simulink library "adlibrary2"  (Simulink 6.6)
undefined symbols (not defined in the file or in its folder): adlibrary2, ADM, DDRII, DRAM, II, no_bitstream, SRAM, SX, XP, XRC
libraries: xbsIndex_r4 x430, adlibrary2 x11, adlibrary2_ddr2dram5t1_1 x6, adlibrary2_d2sram_0 x5, adlibrary2_ddr2dram_1 x4, adlibrary2_ddr_xpi0 x4, adlibrary2_ddr_xpl x3, adlibrary2_xpl32 x1, adlibrary2_xpl64 x1, adlibrary2_zbt64 x1, adlibrary2_zbt4_0 x1, adlibrary2_zbt4_1 x1
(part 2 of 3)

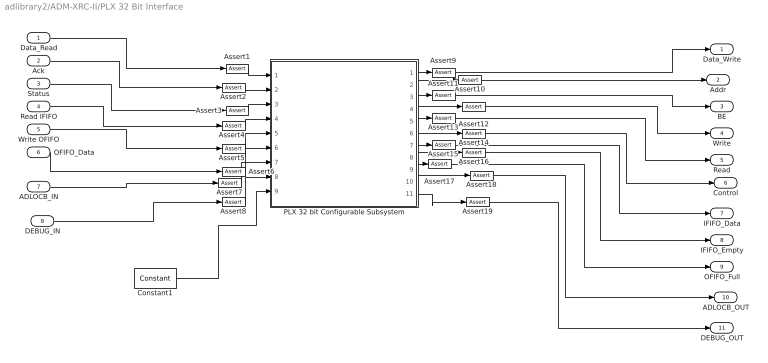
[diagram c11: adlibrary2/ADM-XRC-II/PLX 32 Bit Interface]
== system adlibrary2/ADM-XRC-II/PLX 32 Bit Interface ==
  Data_Read : Inport
  Ack : Inport  Port=2
  Status : Inport  Port=3
  Read IFIFO : Inport  Port=4
  Write OFIFO : Inport  Port=5
  OFIFO_Data : Inport  Port=6
  ADLOCB_IN : Inport  Port=7
  DEBUG_IN : Inport  Port=8
  Assert{1..19} (19 alike) : xbsIndex_r4/Assert  assert_type=off  type_source=Explicitly  arith_type="Signed  (2's comp)"  n_bits=16  bin_pt=14  assert_rate=on  rate_source=Explicitly  period=ad_get_simulink_period  output_port=on  block_type=assert
  Constant1 : xbsIndex_r4/Constant  arith_type=Boolean  const=sstep_clk_sel_default  n_bits=16  bin_pt=14  explicit_period=on  period=ad_get_simulink_period  equ=P=C  opselect=C  inp2=PCIN>>17  opr=+  inp1=P  carry=CIN  dbl_ovrd=off  block_type=constant
  PLX 32 bit Configurable Subsystem : Subsystem  Tag=configX  BlockChoice=PLX 32Bit Simulation  mask{program=program, clock_ratio=clock_ratio}
      mask prompts: program "Local Bus Script Program"; clock_ratio "Clock Ratio"
  Data_Write : Outport
  Addr : Outport  Port=2
  BE : Outport  Port=3
  Write : Outport  Port=4
  Read : Outport  Port=5
  Control : Outport  Port=6
  IFIFO_Data : Outport  Port=7
  IFIFO_Empty : Outport  Port=8
  OFIFO_Full : Outport  Port=9
  ADLOCB_OUT : Outport  Port=10
  DEBUG_OUT : Outport  Port=11
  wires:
  PLX 32 bit Configurable Subsystem/1(Data_Write) -> Assert9/1
  PLX 32 bit Configurable Subsystem/2(Addr) -> Assert10/1
  PLX 32 bit Configurable Subsystem/4(Write) -> Assert12/1
  PLX 32 bit Configurable Subsystem/6(Control) -> Assert14/1
  PLX 32 bit Configurable Subsystem/7(IFIFO_Data) -> Assert15/1
  PLX 32 bit Configurable Subsystem/8(IFIFO_Empty) -> Assert16/1
  PLX 32 bit Configurable Subsystem/9(OFIFO_Full) -> Assert17/1
  PLX 32 bit Configurable Subsystem/3(BE) -> Assert11/1
  PLX 32 bit Configurable Subsystem/10(ADLOCB_OUT) -> Assert18/1
  Data_Read/1 -> Assert1/1
  Ack/1 -> Assert2/1
  Status/1 -> Assert3/1
  Read IFIFO/1 -> Assert4/1
  Write OFIFO/1 -> Assert5/1
  OFIFO_Data/1 -> Assert6/1
  ADLOCB_IN/1 -> Assert7/1
  PLX 32 bit Configurable Subsystem/5(Read) -> Assert13/1
  Assert1/1 -> PLX 32 bit Configurable Subsystem/1(Data_Read)
  Assert2/1 -> PLX 32 bit Configurable Subsystem/2(Ack)
  Assert3/1 -> PLX 32 bit Configurable Subsystem/3(Status)
  Assert4/1 -> PLX 32 bit Configurable Subsystem/4(Read IFIFO)
  Assert5/1 -> PLX 32 bit Configurable Subsystem/5(Write OFIFO)
  Assert6/1 -> PLX 32 bit Configurable Subsystem/6(OFIFO_Data)
  Assert7/1 -> PLX 32 bit Configurable Subsystem/7(ADLOCB_IN)
  Assert9/1 -> Data_Write/1
  Assert10/1 -> Addr/1
  Assert11/1 -> BE/1
  Assert12/1 -> Write/1
  Assert13/1 -> Read/1
  Assert14/1 -> Control/1
  Assert15/1 -> IFIFO_Data/1
  Assert16/1 -> IFIFO_Empty/1
  Assert17/1 -> OFIFO_Full/1
  Assert18/1 -> ADLOCB_OUT/1
  DEBUG_IN/1 -> Assert8/1
  PLX 32 bit Configurable Subsystem/11(DEBUG_OUT) -> Assert19/1
  Assert19/1 -> DEBUG_OUT/1
  Assert8/1 -> PLX 32 bit Configurable Subsystem/8(DEBUG_IN)
  Constant1/1 -> PLX 32 bit Configurable Subsystem/9(sstep_clk_sel_default)

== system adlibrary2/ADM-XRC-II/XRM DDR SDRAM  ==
  cache_data_in : Inport
  cache_addr : Inport  Port=2
  cache_write : Inport  Port=3
  ddr_page : Inport  Port=4
  ddr_addr : Inport  Port=5
  ddr_read : Inport  Port=6
  ddr_write : Inport  Port=7
  Assert{1..9} (9 alike) : xbsIndex_r4/Assert  assert_type=off  type_source=Explicitly  arith_type="Signed  (2's comp)"  n_bits=16  bin_pt=14  assert_rate=on  rate_source=Explicitly  period=ad_get_simulink_period  output_port=on  block_type=assert
  Configurable Subsystem : Subsystem  Tag=configX  BlockChoice=DDR SDRAM 64bit Simulation
  cache_data_out : Outport
  ddr_busy : Outport  Port=2
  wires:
  cache_data_in/1 -> Assert1/1
  cache_addr/1 -> Assert2/1
  cache_write/1 -> Assert3/1
  ddr_page/1 -> Assert4/1
  ddr_addr/1 -> Assert5/1
  ddr_read/1 -> Assert6/1
  ddr_write/1 -> Assert7/1
  Configurable Subsystem/1(cache_data_out) -> Assert8/1
  Configurable Subsystem/2(ddr_busy) -> Assert9/1
  Assert1/1 -> Configurable Subsystem/1(cache_data_in)
  Assert2/1 -> Configurable Subsystem/2(cache_addr)
  Assert3/1 -> Configurable Subsystem/3(cache_write)
  Assert4/1 -> Configurable Subsystem/4(ddr_page)
  Assert5/1 -> Configurable Subsystem/5(ddr_addr)
  Assert6/1 -> Configurable Subsystem/6(ddr_read)
  Assert7/1 -> Configurable Subsystem/7(ddr_write)
  Assert8/1 -> cache_data_out/1
  Assert9/1 -> ddr_busy/1

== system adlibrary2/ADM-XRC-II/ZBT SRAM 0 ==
  d : Inport
  a : Inport  Port=2
  w : Inport  Port=3
  r : Inport  Port=4
  be : Inport  Port=5
  adlocb_in : Inport  Port=6
  Assert{,1..8} (9 alike) : xbsIndex_r4/Assert  assert_type=off  type_source=Explicitly  arith_type="Signed  (2's comp)"  n_bits=16  bin_pt=14  assert_rate=on  rate_source=Explicitly  period=ad_get_simulink_period  output_port=on  block_type=assert
  Configurable Subsystem : Subsystem  Tag=configX  BlockChoice=ZBT SRAM 32Bit Simulation
  q : Outport
  qv : Outport  Port=2
  adlocb_out : Outport  Port=3
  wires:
  d/1 -> Assert/1
  a/1 -> Assert1/1
  w/1 -> Assert2/1
  r/1 -> Assert4/1
  be/1 -> Assert3/1
  adlocb_in/1 -> Assert5/1
  Configurable Subsystem/1(q) -> Assert6/1
  Configurable Subsystem/2(qv) -> Assert7/1
  Configurable Subsystem/3(adlocb_out) -> Assert8/1
  Assert/1 -> Configurable Subsystem/1(d)
  Assert1/1 -> Configurable Subsystem/2(a)
  Assert2/1 -> Configurable Subsystem/3(w)
  Assert4/1 -> Configurable Subsystem/4(r)
  Assert3/1 -> Configurable Subsystem/5(be)
  Assert5/1 -> Configurable Subsystem/6(adlocb_in)
  Assert8/1 -> adlocb_out/1
  Assert7/1 -> qv/1
  Assert6/1 -> q/1

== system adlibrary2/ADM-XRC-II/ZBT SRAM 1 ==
  d : Inport
  a : Inport  Port=2
  w : Inport  Port=3
  r : Inport  Port=4
  be : Inport  Port=5
  adlocb_in : Inport  Port=6
  Assert{,1..8} (9 alike) : xbsIndex_r4/Assert  assert_type=off  type_source=Explicitly  arith_type="Signed  (2's comp)"  n_bits=16  bin_pt=14  assert_rate=on  rate_source=Explicitly  period=ad_get_simulink_period  output_port=on  block_type=assert
  Configurable Subsystem : Subsystem  Tag=configX  BlockChoice=ZBT SRAM 32Bit Simulation
  q : Outport
  qv : Outport  Port=2
  adlocb_out : Outport  Port=3
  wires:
  Configurable Subsystem/3(adlocb_out) -> Assert8/1
  Configurable Subsystem/2(qv) -> Assert7/1
  Configurable Subsystem/1(q) -> Assert6/1
  adlocb_in/1 -> Assert5/1
  be/1 -> Assert4/1
  r/1 -> Assert3/1
  w/1 -> Assert2/1
  a/1 -> Assert1/1
  d/1 -> Assert/1
  Assert/1 -> Configurable Subsystem/1(d)
  Assert1/1 -> Configurable Subsystem/2(a)
  Assert2/1 -> Configurable Subsystem/3(w)
  Assert3/1 -> Configurable Subsystem/4(r)
  Assert4/1 -> Configurable Subsystem/5(be)
  Assert5/1 -> Configurable Subsystem/6(adlocb_in)
  Assert6/1 -> q/1
  Assert7/1 -> qv/1
  Assert8/1 -> adlocb_out/1

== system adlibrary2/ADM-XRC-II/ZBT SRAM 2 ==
  d : Inport
  a : Inport  Port=2
  w : Inport  Port=3
  r : Inport  Port=4
  be : Inport  Port=5
  adlocb_in : Inport  Port=6
  Assert{,1..8} (9 alike) : xbsIndex_r4/Assert  assert_type=off  type_source=Explicitly  arith_type="Signed  (2's comp)"  n_bits=16  bin_pt=14  assert_rate=on  rate_source=Explicitly  period=ad_get_simulink_period  output_port=on  block_type=assert
  Configurable Subsystem : Subsystem  Tag=configX  BlockChoice=ZBT SRAM 32Bit Simulation
  q : Outport
  qv : Outport  Port=2
  adlocb_out : Outport  Port=3
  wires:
  Configurable Subsystem/3(adlocb_out) -> Assert8/1
  Configurable Subsystem/2(qv) -> Assert7/1
  Configurable Subsystem/1(q) -> Assert6/1
  adlocb_in/1 -> Assert5/1
  be/1 -> Assert4/1
  r/1 -> Assert3/1
  w/1 -> Assert2/1
  a/1 -> Assert1/1
  d/1 -> Assert/1
  Assert/1 -> Configurable Subsystem/1(d)
  Assert1/1 -> Configurable Subsystem/2(a)
  Assert2/1 -> Configurable Subsystem/3(w)
  Assert3/1 -> Configurable Subsystem/4(r)
  Assert4/1 -> Configurable Subsystem/5(be)
  Assert5/1 -> Configurable Subsystem/6(adlocb_in)
  Assert6/1 -> q/1
  Assert7/1 -> qv/1
  Assert8/1 -> adlocb_out/1

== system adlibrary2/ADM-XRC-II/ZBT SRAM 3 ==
  d : Inport
  a : Inport  Port=2
  w : Inport  Port=3
  r : Inport  Port=4
  be : Inport  Port=5
  adlocb_in : Inport  Port=6
  Assert{,1..8} (9 alike) : xbsIndex_r4/Assert  assert_type=off  type_source=Explicitly  arith_type="Signed  (2's comp)"  n_bits=16  bin_pt=14  assert_rate=on  rate_source=Explicitly  period=ad_get_simulink_period  output_port=on  block_type=assert
  Configurable Subsystem : Subsystem  Tag=configX  BlockChoice=ZBT SRAM 32Bit Simulation
  q : Outport
  qv : Outport  Port=2
  adlocb_out : Outport  Port=3
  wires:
  Configurable Subsystem/3(adlocb_out) -> Assert7/1
  Configurable Subsystem/2(qv) -> Assert6/1
  Configurable Subsystem/1(q) -> Assert8/1
  adlocb_in/1 -> Assert5/1
  be/1 -> Assert4/1
  r/1 -> Assert3/1
  w/1 -> Assert2/1
  a/1 -> Assert1/1
  d/1 -> Assert/1
  Assert/1 -> Configurable Subsystem/1(d)
  Assert1/1 -> Configurable Subsystem/2(a)
  Assert2/1 -> Configurable Subsystem/3(w)
  Assert3/1 -> Configurable Subsystem/4(r)
  Assert4/1 -> Configurable Subsystem/5(be)
  Assert5/1 -> Configurable Subsystem/6(adlocb_in)
  Assert8/1 -> q/1
  Assert6/1 -> qv/1
  ? -> adlocb_out/1

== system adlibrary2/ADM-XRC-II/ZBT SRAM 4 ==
  d : Inport
  a : Inport  Port=2
  w : Inport  Port=3
  r : Inport  Port=4
  be : Inport  Port=5
  adlocb_in : Inport  Port=6
  Assert{,1..8} (9 alike) : xbsIndex_r4/Assert  assert_type=off  type_source=Explicitly  arith_type="Signed  (2's comp)"  n_bits=16  bin_pt=14  assert_rate=on  rate_source=Explicitly  period=ad_get_simulink_period  output_port=on  block_type=assert
  Configurable Subsystem : Subsystem  Tag=configX  BlockChoice=ZBT SRAM 32Bit Simulation
  q : Outport
  qv : Outport  Port=2
  adlocb_out : Outport  Port=3
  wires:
  Configurable Subsystem/3(adlocb_out) -> Assert8/1
  Configurable Subsystem/2(qv) -> Assert7/1
  Configurable Subsystem/1(q) -> Assert6/1
  adlocb_in/1 -> Assert5/1
  be/1 -> Assert4/1
  r/1 -> Assert3/1
  w/1 -> Assert2/1
  a/1 -> Assert1/1
  d/1 -> Assert/1
  Assert/1 -> Configurable Subsystem/1(d)
  Assert1/1 -> Configurable Subsystem/2(a)
  Assert2/1 -> Configurable Subsystem/3(w)
  Assert3/1 -> Configurable Subsystem/4(r)
  Assert4/1 -> Configurable Subsystem/5(be)
  Assert5/1 -> Configurable Subsystem/6(adlocb_in)
  Assert6/1 -> q/1
  Assert7/1 -> qv/1
  Assert8/1 -> adlocb_out/1

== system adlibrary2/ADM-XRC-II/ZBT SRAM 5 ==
  d : Inport
  a : Inport  Port=2
  w : Inport  Port=3
  r : Inport  Port=4
  be : Inport  Port=5
  adlocb_in : Inport  Port=6
  Assert{,1..8} (9 alike) : xbsIndex_r4/Assert  assert_type=off  type_source=Explicitly  arith_type="Signed  (2's comp)"  n_bits=16  bin_pt=14  assert_rate=on  rate_source=Explicitly  period=ad_get_simulink_period  output_port=on  block_type=assert
  Configurable Subsystem : Subsystem  Tag=configX  BlockChoice=ZBT SRAM 32Bit Simulation
  q : Outport
  qv : Outport  Port=2
  adlocb_out : Outport  Port=3
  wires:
  Configurable Subsystem/3(adlocb_out) -> Assert8/1
  Configurable Subsystem/2(qv) -> Assert7/1
  Configurable Subsystem/1(q) -> Assert6/1
  adlocb_in/1 -> Assert5/1
  be/1 -> Assert4/1
  r/1 -> Assert3/1
  w/1 -> Assert2/1
  a/1 -> Assert1/1
  d/1 -> Assert/1
  Assert/1 -> Configurable Subsystem/1(d)
  Assert1/1 -> Configurable Subsystem/2(a)
  Assert2/1 -> Configurable Subsystem/3(w)
  Assert3/1 -> Configurable Subsystem/4(r)
  Assert4/1 -> Configurable Subsystem/5(be)
  Assert5/1 -> Configurable Subsystem/6(adlocb_in)
  Assert6/1 -> q/1
  Assert7/1 -> qv/1
  Assert8/1 -> adlocb_out/1

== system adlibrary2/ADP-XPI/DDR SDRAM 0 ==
  cache_data_in : Inport
  cache_addr : Inport  Port=2
  cache_write : Inport  Port=3
  ddr_page : Inport  Port=4
  ddr_addr : Inport  Port=5
  ddr_read : Inport  Port=6
  ddr_write : Inport  Port=7
  Assert{1..7,9..10} (9 alike) : xbsIndex_r4/Assert  assert_type=off  type_source=Explicitly  arith_type="Signed  (2's comp)"  n_bits=16  bin_pt=14  assert_rate=on  rate_source=Explicitly  period=ad_get_simulink_period  output_port=on  block_type=assert
  Configurable Subsystem : Subsystem  Tag=configX  BlockChoice=DDR SDRAM 64bit Simulation  mask{memsize=memsize}
      mask prompts: memsize "Simulation Ram Size (Mb)"
  cache_data_out : Outport
  ddr_busy : Outport  Port=2
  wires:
  Assert10/1 -> ddr_busy/1
  Assert9/1 -> cache_data_out/1
  Assert6/1 -> Configurable Subsystem/6(ddr_read)
  Assert5/1 -> Configurable Subsystem/5(ddr_addr)
  Assert4/1 -> Configurable Subsystem/4(ddr_page)
  Assert3/1 -> Configurable Subsystem/3(cache_write)
  Assert2/1 -> Configurable Subsystem/2(cache_addr)
  Assert1/1 -> Configurable Subsystem/1(cache_data_in)
  ddr_write/1 -> Assert7/1
  ddr_read/1 -> Assert6/1
  ddr_addr/1 -> Assert5/1
  ddr_page/1 -> Assert4/1
  cache_write/1 -> Assert3/1
  cache_addr/1 -> Assert2/1
  cache_data_in/1 -> Assert1/1
  Configurable Subsystem/1(cache_data_out) -> Assert9/1
  Configurable Subsystem/2(ddr_busy) -> Assert10/1
  Assert7/1 -> Configurable Subsystem/7(ddr_write)

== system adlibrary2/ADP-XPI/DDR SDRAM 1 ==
  cache_data_in : Inport
  cache_addr : Inport  Port=2
  cache_write : Inport  Port=3
  ddr_page : Inport  Port=4
  ddr_addr : Inport  Port=5
  ddr_read : Inport  Port=6
  ddr_write : Inport  Port=7
  Assert{1..7,9..10} (9 alike) : xbsIndex_r4/Assert  assert_type=off  type_source=Explicitly  arith_type="Signed  (2's comp)"  n_bits=16  bin_pt=14  assert_rate=on  rate_source=Explicitly  period=ad_get_simulink_period  output_port=on  block_type=assert
  Configurable Subsystem : Subsystem  Tag=configX  BlockChoice=DDR SDRAM 64bit Simulation  mask{memsize=memsize}
      mask prompts: memsize "Simulation Ram Size (Mb)"
  cache_data_out : Outport
  ddr_busy : Outport  Port=2
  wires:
  Assert7/1 -> Configurable Subsystem/7(ddr_write)
  Configurable Subsystem/2(ddr_busy) -> Assert10/1
  Configurable Subsystem/1(cache_data_out) -> Assert9/1
  cache_data_in/1 -> Assert1/1
  cache_addr/1 -> Assert2/1
  cache_write/1 -> Assert3/1
  ddr_page/1 -> Assert4/1
  ddr_addr/1 -> Assert5/1
  ddr_read/1 -> Assert6/1
  ddr_write/1 -> Assert7/1
  Assert1/1 -> Configurable Subsystem/1(cache_data_in)
  Assert2/1 -> Configurable Subsystem/2(cache_addr)
  Assert3/1 -> Configurable Subsystem/3(cache_write)
  Assert4/1 -> Configurable Subsystem/4(ddr_page)
  Assert5/1 -> Configurable Subsystem/5(ddr_addr)
  Assert6/1 -> Configurable Subsystem/6(ddr_read)
  Assert9/1 -> cache_data_out/1
  Assert10/1 -> ddr_busy/1

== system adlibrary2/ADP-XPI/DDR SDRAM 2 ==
  cache_data_in : Inport
  cache_addr : Inport  Port=2
  cache_write : Inport  Port=3
  ddr_page : Inport  Port=4
  ddr_addr : Inport  Port=5
  ddr_read : Inport  Port=6
  ddr_write : Inport  Port=7
  Assert{1..7,9..10} (9 alike) : xbsIndex_r4/Assert  assert_type=off  type_source=Explicitly  arith_type="Signed  (2's comp)"  n_bits=16  bin_pt=14  assert_rate=on  rate_source=Explicitly  period=ad_get_simulink_period  output_port=on  block_type=assert
  Configurable Subsystem : Subsystem  Tag=configX  BlockChoice=DDR SDRAM 64bit Simulation  mask{memsize=memsize}
      mask prompts: memsize "Simulation Ram Size (Mb)"
  cache_data_out : Outport
  ddr_busy : Outport  Port=2
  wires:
  Assert10/1 -> ddr_busy/1
  Assert9/1 -> cache_data_out/1
  Assert6/1 -> Configurable Subsystem/6(ddr_read)
  Assert5/1 -> Configurable Subsystem/5(ddr_addr)
  Assert4/1 -> Configurable Subsystem/4(ddr_page)
  Assert3/1 -> Configurable Subsystem/3(cache_write)
  Assert2/1 -> Configurable Subsystem/2(cache_addr)
  Assert1/1 -> Configurable Subsystem/1(cache_data_in)
  ddr_write/1 -> Assert7/1
  ddr_read/1 -> Assert6/1
  ddr_addr/1 -> Assert5/1
  ddr_page/1 -> Assert4/1
  cache_write/1 -> Assert3/1
  cache_addr/1 -> Assert2/1
  cache_data_in/1 -> Assert1/1
  Configurable Subsystem/1(cache_data_out) -> Assert9/1
  Configurable Subsystem/2(ddr_busy) -> Assert10/1
  Assert7/1 -> Configurable Subsystem/7(ddr_write)

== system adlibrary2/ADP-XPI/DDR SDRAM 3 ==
  cache_data_in : Inport
  cache_addr : Inport  Port=2
  cache_write : Inport  Port=3
  ddr_page : Inport  Port=4
  ddr_addr : Inport  Port=5
  ddr_read : Inport  Port=6
  ddr_write : Inport  Port=7
  Assert{1..7,9..10} (9 alike) : xbsIndex_r4/Assert  assert_type=off  type_source=Explicitly  arith_type="Signed  (2's comp)"  n_bits=16  bin_pt=14  assert_rate=on  rate_source=Explicitly  period=ad_get_simulink_period  output_port=on  block_type=assert
  Configurable Subsystem : Subsystem  Tag=configX  BlockChoice=DDR SDRAM 64bit Simulation  mask{memsize=memsize}
      mask prompts: memsize "Simulation Ram Size (Mb)"
  cache_data_out : Outport
  ddr_busy : Outport  Port=2
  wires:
  Assert7/1 -> Configurable Subsystem/7(ddr_write)
  Configurable Subsystem/2(ddr_busy) -> Assert10/1
  Configurable Subsystem/1(cache_data_out) -> Assert9/1
  cache_data_in/1 -> Assert1/1
  cache_addr/1 -> Assert2/1
  cache_write/1 -> Assert3/1
  ddr_page/1 -> Assert4/1
  ddr_addr/1 -> Assert5/1
  ddr_read/1 -> Assert6/1
  ddr_write/1 -> Assert7/1
  Assert1/1 -> Configurable Subsystem/1(cache_data_in)
  Assert2/1 -> Configurable Subsystem/2(cache_addr)
  Assert3/1 -> Configurable Subsystem/3(cache_write)
  Assert4/1 -> Configurable Subsystem/4(ddr_page)
  Assert5/1 -> Configurable Subsystem/5(ddr_addr)
  Assert6/1 -> Configurable Subsystem/6(ddr_read)
  Assert9/1 -> cache_data_out/1
  Assert10/1 -> ddr_busy/1

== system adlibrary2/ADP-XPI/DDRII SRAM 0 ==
  d : Inport
  a : Inport  Port=2
  w : Inport  Port=3
  r : Inport  Port=4
  be : Inport  Port=5
  adlocb_in : Inport  Port=6
  Assert{1..9} (9 alike) : xbsIndex_r4/Assert  assert_type=off  type_source=Explicitly  arith_type="Signed  (2's comp)"  n_bits=16  bin_pt=14  assert_rate=on  rate_source=Explicitly  period=ad_get_simulink_period  output_port=on  block_type=assert
  Configurable Subsystem : Subsystem  Tag=configX  BlockChoice=DDRII SRAM Simulation
  q : Outport
  qv : Outport  Port=2
  adlocb_out : Outport  Port=3
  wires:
  Assert9/1 -> adlocb_out/1
  Assert8/1 -> qv/1
  Assert7/1 -> q/1
  Assert6/1 -> Configurable Subsystem/6(adlocb_in)
  Assert5/1 -> Configurable Subsystem/5(be)
  Assert4/1 -> Configurable Subsystem/4(r)
  Assert3/1 -> Configurable Subsystem/3(w)
  Assert2/1 -> Configurable Subsystem/2(a)
  Assert1/1 -> Configurable Subsystem/1(d)
  Configurable Subsystem/2(qv) -> Assert8/1
  Configurable Subsystem/3(adlocb_out) -> Assert9/1
  adlocb_in/1 -> Assert6/1
  be/1 -> Assert5/1
  r/1 -> Assert4/1
  w/1 -> Assert3/1
  a/1 -> Assert2/1
  d/1 -> Assert1/1
  Configurable Subsystem/1(q) -> Assert7/1

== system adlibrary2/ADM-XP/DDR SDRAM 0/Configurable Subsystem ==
  cache_data_in : Inport
  cache_addr : Inport  Port=2
  cache_write : Inport  Port=3
  ddr_page : Inport  Port=4
  ddr_addr : Inport  Port=5
  ddr_read : Inport  Port=6
  ddr_write : Inport  Port=7
  adlocb_in : Inport  Port=8
  DDR SDRAM 32bit Simulation : adlibrary2_ddr_xpl/DDR SDRAM 32bit Simulation  SystemSampleTime=-1  memsize=memsize
  cache_data_out : Outport
  ddr_busy : Outport  Port=2
  adlocb_out : Outport  Port=3
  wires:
  cache_data_in/1 -> DDR SDRAM 32bit Simulation/1
  cache_addr/1 -> DDR SDRAM 32bit Simulation/2
  cache_write/1 -> DDR SDRAM 32bit Simulation/3
  ddr_page/1 -> DDR SDRAM 32bit Simulation/4
  ddr_addr/1 -> DDR SDRAM 32bit Simulation/5
  ddr_read/1 -> DDR SDRAM 32bit Simulation/6
  ddr_write/1 -> DDR SDRAM 32bit Simulation/7
  adlocb_in/1 -> DDR SDRAM 32bit Simulation/8
  DDR SDRAM 32bit Simulation/1 -> cache_data_out/1
  DDR SDRAM 32bit Simulation/2 -> ddr_busy/1
  DDR SDRAM 32bit Simulation/3 -> adlocb_out/1

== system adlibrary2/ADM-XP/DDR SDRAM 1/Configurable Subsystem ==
  cache_data_in : Inport
  cache_addr : Inport  Port=2
  cache_write : Inport  Port=3
  ddr_page : Inport  Port=4
  ddr_addr : Inport  Port=5
  ddr_read : Inport  Port=6
  ddr_write : Inport  Port=7
  adlocb_in : Inport  Port=8
  DDR SDRAM 32bit Simulation : adlibrary2_ddr_xpl/DDR SDRAM 32bit Simulation  SystemSampleTime=-1  memsize=memsize
  cache_data_out : Outport
  ddr_busy : Outport  Port=2
  adlocb_out : Outport  Port=3
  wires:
  cache_data_in/1 -> DDR SDRAM 32bit Simulation/1
  cache_addr/1 -> DDR SDRAM 32bit Simulation/2
  cache_write/1 -> DDR SDRAM 32bit Simulation/3
  ddr_page/1 -> DDR SDRAM 32bit Simulation/4
  ddr_addr/1 -> DDR SDRAM 32bit Simulation/5
  ddr_read/1 -> DDR SDRAM 32bit Simulation/6
  ddr_write/1 -> DDR SDRAM 32bit Simulation/7
  adlocb_in/1 -> DDR SDRAM 32bit Simulation/8
  DDR SDRAM 32bit Simulation/1 -> cache_data_out/1
  DDR SDRAM 32bit Simulation/2 -> ddr_busy/1
  DDR SDRAM 32bit Simulation/3 -> adlocb_out/1

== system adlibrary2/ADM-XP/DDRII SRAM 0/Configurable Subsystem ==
  d : Inport
  a : Inport  Port=2
  w : Inport  Port=3
  r : Inport  Port=4
  be : Inport  Port=5
  adlocb_in : Inport  Port=6
  DDRII SRAM Simulation : adlibrary2_d2sram_0/DDRII SRAM Simulation  SystemSampleTime=-1
  q : Outport
  qv : Outport  Port=2
  adlocb_out : Outport  Port=3
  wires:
  d/1 -> DDRII SRAM Simulation/1
  a/1 -> DDRII SRAM Simulation/2
  w/1 -> DDRII SRAM Simulation/3
  r/1 -> DDRII SRAM Simulation/4
  be/1 -> DDRII SRAM Simulation/5
  adlocb_in/1 -> DDRII SRAM Simulation/6
  DDRII SRAM Simulation/1 -> q/1
  DDRII SRAM Simulation/2 -> qv/1
  DDRII SRAM Simulation/3 -> adlocb_out/1

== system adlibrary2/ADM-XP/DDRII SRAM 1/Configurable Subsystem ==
  d : Inport
  a : Inport  Port=2
  w : Inport  Port=3
  r : Inport  Port=4
  be : Inport  Port=5
  adlocb_in : Inport  Port=6
  DDRII SRAM Simulation : adlibrary2_d2sram_0/DDRII SRAM Simulation  SystemSampleTime=-1
  q : Outport
  qv : Outport  Port=2
  adlocb_out : Outport  Port=3
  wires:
  d/1 -> DDRII SRAM Simulation/1
  a/1 -> DDRII SRAM Simulation/2
  w/1 -> DDRII SRAM Simulation/3
  r/1 -> DDRII SRAM Simulation/4
  be/1 -> DDRII SRAM Simulation/5
  adlocb_in/1 -> DDRII SRAM Simulation/6
  DDRII SRAM Simulation/1 -> q/1
  DDRII SRAM Simulation/2 -> qv/1
  DDRII SRAM Simulation/3 -> adlocb_out/1

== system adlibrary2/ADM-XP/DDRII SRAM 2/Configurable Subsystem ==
  d : Inport
  a : Inport  Port=2
  w : Inport  Port=3
  r : Inport  Port=4
  be : Inport  Port=5
  adlocb_in : Inport  Port=6
  DDRII SRAM Simulation : adlibrary2_d2sram_0/DDRII SRAM Simulation  SystemSampleTime=-1
  q : Outport
  qv : Outport  Port=2
  adlocb_out : Outport  Port=3
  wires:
  d/1 -> DDRII SRAM Simulation/1
  a/1 -> DDRII SRAM Simulation/2
  w/1 -> DDRII SRAM Simulation/3
  r/1 -> DDRII SRAM Simulation/4
  be/1 -> DDRII SRAM Simulation/5
  adlocb_in/1 -> DDRII SRAM Simulation/6
  DDRII SRAM Simulation/1 -> q/1
  DDRII SRAM Simulation/2 -> qv/1
  DDRII SRAM Simulation/3 -> adlocb_out/1

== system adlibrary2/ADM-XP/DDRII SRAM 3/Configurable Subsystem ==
  d : Inport
  a : Inport  Port=2
  w : Inport  Port=3
  r : Inport  Port=4
  be : Inport  Port=5
  adlocb_in : Inport  Port=6
  DDRII SRAM Simulation : adlibrary2_d2sram_0/DDRII SRAM Simulation  SystemSampleTime=-1
  q : Outport
  qv : Outport  Port=2
  adlocb_out : Outport  Port=3
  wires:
  d/1 -> DDRII SRAM Simulation/1
  a/1 -> DDRII SRAM Simulation/2
  w/1 -> DDRII SRAM Simulation/3
  r/1 -> DDRII SRAM Simulation/4
  be/1 -> DDRII SRAM Simulation/5
  adlocb_in/1 -> DDRII SRAM Simulation/6
  DDRII SRAM Simulation/1 -> q/1
  DDRII SRAM Simulation/2 -> qv/1
  DDRII SRAM Simulation/3 -> adlocb_out/1

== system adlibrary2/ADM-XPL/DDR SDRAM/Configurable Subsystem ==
  cache_data_in : Inport
  cache_addr : Inport  Port=2
  cache_write : Inport  Port=3
  ddr_page : Inport  Port=4
  ddr_addr : Inport  Port=5
  ddr_read : Inport  Port=6
  ddr_write : Inport  Port=7
  adlocb_in : Inport  Port=8
  DDR SDRAM 32bit Simulation : adlibrary2_ddr_xpl/DDR SDRAM 32bit Simulation  SystemSampleTime=-1  memsize=memsize
  cache_data_out : Outport
  ddr_busy : Outport  Port=2
  adlocb_out : Outport  Port=3
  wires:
  cache_data_in/1 -> DDR SDRAM 32bit Simulation/1
  cache_addr/1 -> DDR SDRAM 32bit Simulation/2
  cache_write/1 -> DDR SDRAM 32bit Simulation/3
  ddr_page/1 -> DDR SDRAM 32bit Simulation/4
  ddr_addr/1 -> DDR SDRAM 32bit Simulation/5
  ddr_read/1 -> DDR SDRAM 32bit Simulation/6
  ddr_write/1 -> DDR SDRAM 32bit Simulation/7
  adlocb_in/1 -> DDR SDRAM 32bit Simulation/8
  DDR SDRAM 32bit Simulation/1 -> cache_data_out/1
  DDR SDRAM 32bit Simulation/2 -> ddr_busy/1
  DDR SDRAM 32bit Simulation/3 -> adlocb_out/1

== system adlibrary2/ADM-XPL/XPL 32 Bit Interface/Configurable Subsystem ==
  Data_Read : Inport
  Ack : Inport  Port=2
  Status : Inport  Port=3
  Read IFIFO : Inport  Port=4
  Write OFIFO : Inport  Port=5
  OFIFO_Data : Inport  Port=6
  ADLOCB_IN : Inport  Port=7
  DEBUG_IN : Inport  Port=8
  sstep_clk_sel_default : Inport  Port=9
  XPL 32Bit Simulation : adlibrary2_xpl32/XPL 32Bit Simulation  SystemSampleTime=-1  program=program  clock_ratio=clock_ratio
  Data_Write : Outport
  Addr : Outport  Port=2
  BE : Outport  Port=3
  Write : Outport  Port=4
  Read : Outport  Port=5
  Control : Outport  Port=6
  IFIFO_Data : Outport  Port=7
  IFIFO_Empty : Outport  Port=8
  OFIFO_Full : Outport  Port=9
  ADLOCB_OUT : Outport  Port=10
  DEBUG_OUT : Outport  Port=11
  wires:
  Data_Read/1 -> XPL 32Bit Simulation/1
  Ack/1 -> XPL 32Bit Simulation/2
  Status/1 -> XPL 32Bit Simulation/3
  Read IFIFO/1 -> XPL 32Bit Simulation/4
  Write OFIFO/1 -> XPL 32Bit Simulation/5
  OFIFO_Data/1 -> XPL 32Bit Simulation/6
  ADLOCB_IN/1 -> XPL 32Bit Simulation/7
  DEBUG_IN/1 -> XPL 32Bit Simulation/8
  sstep_clk_sel_default/1 -> XPL 32Bit Simulation/9
  XPL 32Bit Simulation/1 -> Data_Write/1
  XPL 32Bit Simulation/2 -> Addr/1
  XPL 32Bit Simulation/3 -> BE/1
  XPL 32Bit Simulation/4 -> Write/1
  XPL 32Bit Simulation/5 -> Read/1
  XPL 32Bit Simulation/6 -> Control/1
  XPL 32Bit Simulation/7 -> IFIFO_Data/1
  XPL 32Bit Simulation/8 -> IFIFO_Empty/1
  XPL 32Bit Simulation/9 -> OFIFO_Full/1
  XPL 32Bit Simulation/10 -> ADLOCB_OUT/1
  XPL 32Bit Simulation/11 -> DEBUG_OUT/1

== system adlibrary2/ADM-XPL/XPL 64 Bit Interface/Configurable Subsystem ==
  Data_Read : Inport
  Ack : Inport  Port=2
  Status : Inport  Port=3
  Read IFIFO : Inport  Port=4
  Write OFIFO : Inport  Port=5
  OFIFO_Data : Inport  Port=6
  ADLOCB_IN : Inport  Port=7
  DEBUG_IN : Inport  Port=8
  sstep_clk_sel_default : Inport  Port=9
  XPL 64Bit Simulation : adlibrary2_xpl64/XPL 64Bit Simulation  SystemSampleTime=-1  program=program  clock_ratio=clock_ratio
  Data_Write : Outport
  Addr : Outport  Port=2
  BE : Outport  Port=3
  Write : Outport  Port=4
  Read : Outport  Port=5
  Control : Outport  Port=6
  IFIFO_Data : Outport  Port=7
  IFIFO_Empty : Outport  Port=8
  OFIFO_Full : Outport  Port=9
  ADLOCB_OUT : Outport  Port=10
  DEBUG_OUT : Outport  Port=11
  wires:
  Data_Read/1 -> XPL 64Bit Simulation/1
  Ack/1 -> XPL 64Bit Simulation/2
  Status/1 -> XPL 64Bit Simulation/3
  Read IFIFO/1 -> XPL 64Bit Simulation/4
  Write OFIFO/1 -> XPL 64Bit Simulation/5
  OFIFO_Data/1 -> XPL 64Bit Simulation/6
  ADLOCB_IN/1 -> XPL 64Bit Simulation/7
  DEBUG_IN/1 -> XPL 64Bit Simulation/8
  sstep_clk_sel_default/1 -> XPL 64Bit Simulation/9
  XPL 64Bit Simulation/1 -> Data_Write/1
  XPL 64Bit Simulation/2 -> Addr/1
  XPL 64Bit Simulation/3 -> BE/1
  XPL 64Bit Simulation/4 -> Write/1
  XPL 64Bit Simulation/5 -> Read/1
  XPL 64Bit Simulation/6 -> Control/1
  XPL 64Bit Simulation/7 -> IFIFO_Data/1
  XPL 64Bit Simulation/8 -> IFIFO_Empty/1
  XPL 64Bit Simulation/9 -> OFIFO_Full/1
  XPL 64Bit Simulation/10 -> ADLOCB_OUT/1
  XPL 64Bit Simulation/11 -> DEBUG_OUT/1

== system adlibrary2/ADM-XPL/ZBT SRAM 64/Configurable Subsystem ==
  d : Inport
  a : Inport  Port=2
  w : Inport  Port=3
  r : Inport  Port=4
  be : Inport  Port=5
  adlocb_in : Inport  Port=6
  ZBT SRAM 64bit Simulation : adlibrary2_zbt64/ZBT SRAM 64bit Simulation  SystemSampleTime=-1
  q : Outport
  qv : Outport  Port=2
  adlocb_out : Outport  Port=3
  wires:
  d/1 -> ZBT SRAM 64bit Simulation/1
  a/1 -> ZBT SRAM 64bit Simulation/2
  w/1 -> ZBT SRAM 64bit Simulation/3
  r/1 -> ZBT SRAM 64bit Simulation/4
  be/1 -> ZBT SRAM 64bit Simulation/5
  adlocb_in/1 -> ZBT SRAM 64bit Simulation/6
  ZBT SRAM 64bit Simulation/1 -> q/1
  ZBT SRAM 64bit Simulation/2 -> qv/1
  ZBT SRAM 64bit Simulation/3 -> adlocb_out/1

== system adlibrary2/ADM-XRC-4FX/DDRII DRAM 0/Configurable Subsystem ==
  d : Inport
  a : Inport  Port=2
  w : Inport  Port=3
  r : Inport  Port=4
  be : Inport  Port=5
  adlocb_in : Inport  Port=6
  DDRII DRAM Simulation : adlibrary2_ddr2dram_1/DDRII DRAM Simulation  SystemSampleTime=-1
  q : Outport
  qv : Outport  Port=2
  full : Outport  Port=3
  adlocb_out : Outport  Port=4
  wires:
  d/1 -> DDRII DRAM Simulation/1
  a/1 -> DDRII DRAM Simulation/2
  w/1 -> DDRII DRAM Simulation/3
  r/1 -> DDRII DRAM Simulation/4
  be/1 -> DDRII DRAM Simulation/5
  adlocb_in/1 -> DDRII DRAM Simulation/6
  DDRII DRAM Simulation/1 -> q/1
  DDRII DRAM Simulation/2 -> qv/1
  DDRII DRAM Simulation/3 -> full/1
  DDRII DRAM Simulation/4 -> adlocb_out/1

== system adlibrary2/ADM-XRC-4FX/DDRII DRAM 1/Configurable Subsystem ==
  d : Inport
  a : Inport  Port=2
  w : Inport  Port=3
  r : Inport  Port=4
  be : Inport  Port=5
  adlocb_in : Inport  Port=6
  DDRII DRAM Generation : adlibrary2_ddr2dram_1/DDRII DRAM Generation  SystemSampleTime=-1
  q : Outport
  qv : Outport  Port=2
  full : Outport  Port=3
  adlocb_out : Outport  Port=4
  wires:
  d/1 -> DDRII DRAM Generation/1
  a/1 -> DDRII DRAM Generation/2
  w/1 -> DDRII DRAM Generation/3
  r/1 -> DDRII DRAM Generation/4
  be/1 -> DDRII DRAM Generation/5
  adlocb_in/1 -> DDRII DRAM Generation/6
  DDRII DRAM Generation/1 -> q/1
  DDRII DRAM Generation/2 -> qv/1
  DDRII DRAM Generation/3 -> full/1
  DDRII DRAM Generation/4 -> adlocb_out/1

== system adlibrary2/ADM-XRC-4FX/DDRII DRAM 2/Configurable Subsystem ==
  d : Inport
  a : Inport  Port=2
  w : Inport  Port=3
  r : Inport  Port=4
  be : Inport  Port=5
  adlocb_in : Inport  Port=6
  DDRII DRAM Generation : adlibrary2_ddr2dram_1/DDRII DRAM Generation  SystemSampleTime=-1
  q : Outport
  qv : Outport  Port=2
  full : Outport  Port=3
  adlocb_out : Outport  Port=4
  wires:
  d/1 -> DDRII DRAM Generation/1
  a/1 -> DDRII DRAM Generation/2
  w/1 -> DDRII DRAM Generation/3
  r/1 -> DDRII DRAM Generation/4
  be/1 -> DDRII DRAM Generation/5
  adlocb_in/1 -> DDRII DRAM Generation/6
  DDRII DRAM Generation/1 -> q/1
  DDRII DRAM Generation/2 -> qv/1
  DDRII DRAM Generation/3 -> full/1
  DDRII DRAM Generation/4 -> adlocb_out/1

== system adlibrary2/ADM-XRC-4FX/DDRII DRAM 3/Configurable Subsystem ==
  d : Inport
  a : Inport  Port=2
  w : Inport  Port=3
  r : Inport  Port=4
  be : Inport  Port=5
  adlocb_in : Inport  Port=6
  DDRII DRAM Generation : adlibrary2_ddr2dram_1/DDRII DRAM Generation  SystemSampleTime=-1
  q : Outport
  qv : Outport  Port=2
  full : Outport  Port=3
  adlocb_out : Outport  Port=4
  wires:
  d/1 -> DDRII DRAM Generation/1
  a/1 -> DDRII DRAM Generation/2
  w/1 -> DDRII DRAM Generation/3
  r/1 -> DDRII DRAM Generation/4
  be/1 -> DDRII DRAM Generation/5
  adlocb_in/1 -> DDRII DRAM Generation/6
  DDRII DRAM Generation/1 -> q/1
  DDRII DRAM Generation/2 -> qv/1
  DDRII DRAM Generation/3 -> full/1
  DDRII DRAM Generation/4 -> adlocb_out/1

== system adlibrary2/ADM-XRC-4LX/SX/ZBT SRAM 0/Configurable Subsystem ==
  d : Inport
  a : Inport  Port=2
  w : Inport  Port=3
  r : Inport  Port=4
  be : Inport  Port=5
  adlocb_in : Inport  Port=6
  ZBT SRAM 32Bit Simulation : adlibrary2_zbt4_0/ZBT SRAM 32Bit Simulation  SystemSampleTime=-1
  q : Outport
  qv : Outport  Port=2
  adlocb_out : Outport  Port=3
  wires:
  d/1 -> ZBT SRAM 32Bit Simulation/1
  a/1 -> ZBT SRAM 32Bit Simulation/2
  w/1 -> ZBT SRAM 32Bit Simulation/3
  r/1 -> ZBT SRAM 32Bit Simulation/4
  be/1 -> ZBT SRAM 32Bit Simulation/5
  adlocb_in/1 -> ZBT SRAM 32Bit Simulation/6
  ZBT SRAM 32Bit Simulation/1 -> q/1
  ZBT SRAM 32Bit Simulation/2 -> qv/1
  ZBT SRAM 32Bit Simulation/3 -> adlocb_out/1

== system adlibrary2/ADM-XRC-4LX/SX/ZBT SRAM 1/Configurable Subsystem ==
  d : Inport
  a : Inport  Port=2
  w : Inport  Port=3
  r : Inport  Port=4
  be : Inport  Port=5
  adlocb_in : Inport  Port=6
  ZBT SRAM 32Bit Simulation : adlibrary2_zbt4_1/ZBT SRAM 32Bit Simulation  SystemSampleTime=-1
  q : Outport
  qv : Outport  Port=2
  adlocb_out : Outport  Port=3
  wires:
  d/1 -> ZBT SRAM 32Bit Simulation/1
  a/1 -> ZBT SRAM 32Bit Simulation/2
  w/1 -> ZBT SRAM 32Bit Simulation/3
  r/1 -> ZBT SRAM 32Bit Simulation/4
  be/1 -> ZBT SRAM 32Bit Simulation/5
  adlocb_in/1 -> ZBT SRAM 32Bit Simulation/6
  ZBT SRAM 32Bit Simulation/1 -> q/1
  ZBT SRAM 32Bit Simulation/2 -> qv/1
  ZBT SRAM 32Bit Simulation/3 -> adlocb_out/1

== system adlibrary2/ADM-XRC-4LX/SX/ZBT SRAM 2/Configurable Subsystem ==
  d : Inport
  a : Inport  Port=2
  w : Inport  Port=3
  r : Inport  Port=4
  be : Inport  Port=5
  adlocb_in : Inport  Port=6
  ZBT SRAM 32Bit Simulation : adlibrary2_zbt4_2/ZBT SRAM 32Bit Simulation  SystemSampleTime=-1
  q : Outport
  qv : Outport  Port=2
  adlocb_out : Outport  Port=3
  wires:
  d/1 -> ZBT SRAM 32Bit Simulation/1
  a/1 -> ZBT SRAM 32Bit Simulation/2
  w/1 -> ZBT SRAM 32Bit Simulation/3
  r/1 -> ZBT SRAM 32Bit Simulation/4
  be/1 -> ZBT SRAM 32Bit Simulation/5
  adlocb_in/1 -> ZBT SRAM 32Bit Simulation/6
  ZBT SRAM 32Bit Simulation/1 -> q/1
  ZBT SRAM 32Bit Simulation/2 -> qv/1
  ZBT SRAM 32Bit Simulation/3 -> adlocb_out/1

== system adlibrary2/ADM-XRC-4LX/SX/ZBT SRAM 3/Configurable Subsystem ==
  d : Inport
  a : Inport  Port=2
  w : Inport  Port=3
  r : Inport  Port=4
  be : Inport  Port=5
  adlocb_in : Inport  Port=6
  ZBT SRAM 32Bit Simulation : adlibrary2_zbt4_3/ZBT SRAM 32Bit Simulation  SystemSampleTime=-1
  q : Outport
  qv : Outport  Port=2
  adlocb_out : Outport  Port=3
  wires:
  d/1 -> ZBT SRAM 32Bit Simulation/1
  a/1 -> ZBT SRAM 32Bit Simulation/2
  w/1 -> ZBT SRAM 32Bit Simulation/3
  r/1 -> ZBT SRAM 32Bit Simulation/4
  be/1 -> ZBT SRAM 32Bit Simulation/5
  adlocb_in/1 -> ZBT SRAM 32Bit Simulation/6
  ZBT SRAM 32Bit Simulation/1 -> q/1
  ZBT SRAM 32Bit Simulation/2 -> qv/1
  ZBT SRAM 32Bit Simulation/3 -> adlocb_out/1

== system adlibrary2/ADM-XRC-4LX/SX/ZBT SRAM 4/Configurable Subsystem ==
  d : Inport
  a : Inport  Port=2
  w : Inport  Port=3
  r : Inport  Port=4
  be : Inport  Port=5
  adlocb_in : Inport  Port=6
  ZBT SRAM 32Bit Simulation : adlibrary2_zbt4_4/ZBT SRAM 32Bit Simulation  SystemSampleTime=-1
  q : Outport
  qv : Outport  Port=2
  adlocb_out : Outport  Port=3
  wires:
  d/1 -> ZBT SRAM 32Bit Simulation/1
  a/1 -> ZBT SRAM 32Bit Simulation/2
  w/1 -> ZBT SRAM 32Bit Simulation/3
  r/1 -> ZBT SRAM 32Bit Simulation/4
  be/1 -> ZBT SRAM 32Bit Simulation/5
  adlocb_in/1 -> ZBT SRAM 32Bit Simulation/6
  ZBT SRAM 32Bit Simulation/1 -> q/1
  ZBT SRAM 32Bit Simulation/2 -> qv/1
  ZBT SRAM 32Bit Simulation/3 -> adlocb_out/1

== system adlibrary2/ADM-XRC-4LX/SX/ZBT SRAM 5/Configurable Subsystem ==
  d : Inport
  a : Inport  Port=2
  w : Inport  Port=3
  r : Inport  Port=4
  be : Inport  Port=5
  adlocb_in : Inport  Port=6
  ZBT SRAM 32Bit Simulation : adlibrary2_zbt4_5/ZBT SRAM 32Bit Simulation  SystemSampleTime=-1
  q : Outport
  qv : Outport  Port=2
  adlocb_out : Outport  Port=3
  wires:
  d/1 -> ZBT SRAM 32Bit Simulation/1
  a/1 -> ZBT SRAM 32Bit Simulation/2
  w/1 -> ZBT SRAM 32Bit Simulation/3
  r/1 -> ZBT SRAM 32Bit Simulation/4
  be/1 -> ZBT SRAM 32Bit Simulation/5
  adlocb_in/1 -> ZBT SRAM 32Bit Simulation/6
  ZBT SRAM 32Bit Simulation/1 -> q/1
  ZBT SRAM 32Bit Simulation/2 -> qv/1
  ZBT SRAM 32Bit Simulation/3 -> adlocb_out/1

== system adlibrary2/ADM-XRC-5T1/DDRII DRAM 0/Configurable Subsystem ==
  d : Inport
  a : Inport  Port=2
  w : Inport  Port=3
  r : Inport  Port=4
  be : Inport  Port=5
  adlocb_in : Inport  Port=6
  DDRII DRAM Simulation : adlibrary2_ddr2dram5t1_1/DDRII DRAM Simulation  SystemSampleTime=-1
  q : Outport
  qv : Outport  Port=2
  full : Outport  Port=3
  adlocb_out : Outport  Port=4
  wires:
  d/1 -> DDRII DRAM Simulation/1
  a/1 -> DDRII DRAM Simulation/2
  w/1 -> DDRII DRAM Simulation/3
  r/1 -> DDRII DRAM Simulation/4
  be/1 -> DDRII DRAM Simulation/5
  adlocb_in/1 -> DDRII DRAM Simulation/6
  DDRII DRAM Simulation/1 -> q/1
  DDRII DRAM Simulation/2 -> qv/1
  DDRII DRAM Simulation/3 -> full/1
  DDRII DRAM Simulation/4 -> adlocb_out/1

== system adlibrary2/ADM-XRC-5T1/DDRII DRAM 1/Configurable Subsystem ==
  d : Inport
  a : Inport  Port=2
  w : Inport  Port=3
  r : Inport  Port=4
  be : Inport  Port=5
  adlocb_in : Inport  Port=6
  DDRII DRAM Simulation : adlibrary2_ddr2dram5t1_1/DDRII DRAM Simulation  SystemSampleTime=-1
  q : Outport
  qv : Outport  Port=2
  full : Outport  Port=3
  adlocb_out : Outport  Port=4
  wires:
  d/1 -> DDRII DRAM Simulation/1
  a/1 -> DDRII DRAM Simulation/2
  w/1 -> DDRII DRAM Simulation/3
  r/1 -> DDRII DRAM Simulation/4
  be/1 -> DDRII DRAM Simulation/5
  adlocb_in/1 -> DDRII DRAM Simulation/6
  DDRII DRAM Simulation/1 -> q/1
  DDRII DRAM Simulation/2 -> qv/1
  DDRII DRAM Simulation/3 -> full/1
  DDRII DRAM Simulation/4 -> adlocb_out/1

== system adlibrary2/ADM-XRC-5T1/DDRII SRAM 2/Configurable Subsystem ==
  d : Inport
  a : Inport  Port=2
  w : Inport  Port=3
  r : Inport  Port=4
  be : Inport  Port=5
  adlocb_in : Inport  Port=6
  DDRII DRAM Simulation : adlibrary2_ddr2sram5t1/DDRII DRAM Simulation  SystemSampleTime=-1
  q : Outport
  qv : Outport  Port=2
  full : Outport  Port=3
  adlocb_out : Outport  Port=4
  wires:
  d/1 -> DDRII DRAM Simulation/1
  a/1 -> DDRII DRAM Simulation/2
  w/1 -> DDRII DRAM Simulation/3
  r/1 -> DDRII DRAM Simulation/4
  be/1 -> DDRII DRAM Simulation/5
  adlocb_in/1 -> DDRII DRAM Simulation/6
  DDRII DRAM Simulation/1 -> q/1
  DDRII DRAM Simulation/2 -> qv/1
  DDRII DRAM Simulation/3 -> full/1
  DDRII DRAM Simulation/4 -> adlocb_out/1

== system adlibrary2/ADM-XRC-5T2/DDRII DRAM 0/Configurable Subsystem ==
  d : Inport
  a : Inport  Port=2
  w : Inport  Port=3
  r : Inport  Port=4
  be : Inport  Port=5
  adlocb_in : Inport  Port=6
  DDRII DRAM Simulation : adlibrary2_ddr2dram5t1_1/DDRII DRAM Simulation  SystemSampleTime=-1
  q : Outport
  qv : Outport  Port=2
  full : Outport  Port=3
  adlocb_out : Outport  Port=4
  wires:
  d/1 -> DDRII DRAM Simulation/1
  a/1 -> DDRII DRAM Simulation/2
  w/1 -> DDRII DRAM Simulation/3
  r/1 -> DDRII DRAM Simulation/4
  be/1 -> DDRII DRAM Simulation/5
  adlocb_in/1 -> DDRII DRAM Simulation/6
  DDRII DRAM Simulation/1 -> q/1
  DDRII DRAM Simulation/2 -> qv/1
  DDRII DRAM Simulation/3 -> full/1
  DDRII DRAM Simulation/4 -> adlocb_out/1

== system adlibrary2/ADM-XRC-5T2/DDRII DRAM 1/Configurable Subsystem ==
  d : Inport
  a : Inport  Port=2
  w : Inport  Port=3
  r : Inport  Port=4
  be : Inport  Port=5
  adlocb_in : Inport  Port=6
  DDRII DRAM Simulation : adlibrary2_ddr2dram5t1_1/DDRII DRAM Simulation  SystemSampleTime=-1
  q : Outport
  qv : Outport  Port=2
  full : Outport  Port=3
  adlocb_out : Outport  Port=4
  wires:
  d/1 -> DDRII DRAM Simulation/1
  a/1 -> DDRII DRAM Simulation/2
  w/1 -> DDRII DRAM Simulation/3
  r/1 -> DDRII DRAM Simulation/4
  be/1 -> DDRII DRAM Simulation/5
  adlocb_in/1 -> DDRII DRAM Simulation/6
  DDRII DRAM Simulation/1 -> q/1
  DDRII DRAM Simulation/2 -> qv/1
  DDRII DRAM Simulation/3 -> full/1
  DDRII DRAM Simulation/4 -> adlocb_out/1

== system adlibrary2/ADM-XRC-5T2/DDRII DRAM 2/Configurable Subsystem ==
  d : Inport
  a : Inport  Port=2
  w : Inport  Port=3
  r : Inport  Port=4
  be : Inport  Port=5
  adlocb_in : Inport  Port=6
  DDRII DRAM Simulation : adlibrary2_ddr2dram5t1_1/DDRII DRAM Simulation  SystemSampleTime=-1
  q : Outport
  qv : Outport  Port=2
  full : Outport  Port=3
  adlocb_out : Outport  Port=4
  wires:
  d/1 -> DDRII DRAM Simulation/1
  a/1 -> DDRII DRAM Simulation/2
  w/1 -> DDRII DRAM Simulation/3
  r/1 -> DDRII DRAM Simulation/4
  be/1 -> DDRII DRAM Simulation/5
  adlocb_in/1 -> DDRII DRAM Simulation/6
  DDRII DRAM Simulation/1 -> q/1
  DDRII DRAM Simulation/2 -> qv/1
  DDRII DRAM Simulation/3 -> full/1
  DDRII DRAM Simulation/4 -> adlocb_out/1

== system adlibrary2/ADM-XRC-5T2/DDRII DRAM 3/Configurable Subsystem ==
  d : Inport
  a : Inport  Port=2
  w : Inport  Port=3
  r : Inport  Port=4
  be : Inport  Port=5
  adlocb_in : Inport  Port=6
  DDRII DRAM Simulation : adlibrary2_ddr2dram5t1_1/DDRII DRAM Simulation  SystemSampleTime=-1
  q : Outport
  qv : Outport  Port=2
  full : Outport  Port=3
  adlocb_out : Outport  Port=4
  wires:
  d/1 -> DDRII DRAM Simulation/1
  a/1 -> DDRII DRAM Simulation/2
  w/1 -> DDRII DRAM Simulation/3
  r/1 -> DDRII DRAM Simulation/4
  be/1 -> DDRII DRAM Simulation/5
  adlocb_in/1 -> DDRII DRAM Simulation/6
  DDRII DRAM Simulation/1 -> q/1
  DDRII DRAM Simulation/2 -> qv/1
  DDRII DRAM Simulation/3 -> full/1
  DDRII DRAM Simulation/4 -> adlocb_out/1

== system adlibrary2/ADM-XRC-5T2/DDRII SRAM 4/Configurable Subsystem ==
  d : Inport
  a : Inport  Port=2
  w : Inport  Port=3
  r : Inport  Port=4
  be : Inport  Port=5
  adlocb_in : Inport  Port=6
  DDRII DRAM Simulation : adlibrary2_ddr2sram5t2_1/DDRII DRAM Simulation  SystemSampleTime=-1
  q : Outport
  qv : Outport  Port=2
  full : Outport  Port=3
  adlocb_out : Outport  Port=4
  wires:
  d/1 -> DDRII DRAM Simulation/1
  a/1 -> DDRII DRAM Simulation/2
  w/1 -> DDRII DRAM Simulation/3
  r/1 -> DDRII DRAM Simulation/4
  be/1 -> DDRII DRAM Simulation/5
  adlocb_in/1 -> DDRII DRAM Simulation/6
  DDRII DRAM Simulation/1 -> q/1
  DDRII DRAM Simulation/2 -> qv/1
  DDRII DRAM Simulation/3 -> full/1
  DDRII DRAM Simulation/4 -> adlocb_out/1

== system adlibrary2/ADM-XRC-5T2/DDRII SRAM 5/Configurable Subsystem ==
  d : Inport
  a : Inport  Port=2
  w : Inport  Port=3
  r : Inport  Port=4
  be : Inport  Port=5
  adlocb_in : Inport  Port=6
  DDRII DRAM Simulation : adlibrary2_ddr2sram5t2_2/DDRII DRAM Simulation  SystemSampleTime=-1
  q : Outport
  qv : Outport  Port=2
  full : Outport  Port=3
  adlocb_out : Outport  Port=4
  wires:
  d/1 -> DDRII DRAM Simulation/1
  a/1 -> DDRII DRAM Simulation/2
  w/1 -> DDRII DRAM Simulation/3
  r/1 -> DDRII DRAM Simulation/4
  be/1 -> DDRII DRAM Simulation/5
  adlocb_in/1 -> DDRII DRAM Simulation/6
  DDRII DRAM Simulation/1 -> q/1
  DDRII DRAM Simulation/2 -> qv/1
  DDRII DRAM Simulation/3 -> full/1
  DDRII DRAM Simulation/4 -> adlocb_out/1

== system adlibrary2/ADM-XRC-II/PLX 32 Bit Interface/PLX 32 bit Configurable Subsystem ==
  Data_Read : Inport
  Ack : Inport  Port=2
  Status : Inport  Port=3
  Read IFIFO : Inport  Port=4
  Write OFIFO : Inport  Port=5
  OFIFO_Data : Inport  Port=6
  ADLOCB_IN : Inport  Port=7
  DEBUG_IN : Inport  Port=8
  sstep_clk_sel_default : Inport  Port=9
  PLX 32Bit Simulation : adlibrary2_plx32/PLX 32Bit Simulation  SystemSampleTime=-1  program=program  clock_ratio=clock_ratio
  Data_Write : Outport
  Addr : Outport  Port=2
  BE : Outport  Port=3
  Write : Outport  Port=4
  Read : Outport  Port=5
  Control : Outport  Port=6
  IFIFO_Data : Outport  Port=7
  IFIFO_Empty : Outport  Port=8
  OFIFO_Full : Outport  Port=9
  ADLOCB_OUT : Outport  Port=10
  DEBUG_OUT : Outport  Port=11
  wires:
  Data_Read/1 -> PLX 32Bit Simulation/1
  Ack/1 -> PLX 32Bit Simulation/2
  Status/1 -> PLX 32Bit Simulation/3
  Read IFIFO/1 -> PLX 32Bit Simulation/4
  Write OFIFO/1 -> PLX 32Bit Simulation/5
  OFIFO_Data/1 -> PLX 32Bit Simulation/6
  ADLOCB_IN/1 -> PLX 32Bit Simulation/7
  DEBUG_IN/1 -> PLX 32Bit Simulation/8
  sstep_clk_sel_default/1 -> PLX 32Bit Simulation/9
  PLX 32Bit Simulation/1 -> Data_Write/1
  PLX 32Bit Simulation/2 -> Addr/1
  PLX 32Bit Simulation/3 -> BE/1
  PLX 32Bit Simulation/4 -> Write/1
  PLX 32Bit Simulation/5 -> Read/1
  PLX 32Bit Simulation/6 -> Control/1
  PLX 32Bit Simulation/7 -> IFIFO_Data/1
  PLX 32Bit Simulation/8 -> IFIFO_Empty/1
  PLX 32Bit Simulation/9 -> OFIFO_Full/1
  PLX 32Bit Simulation/10 -> ADLOCB_OUT/1
  PLX 32Bit Simulation/11 -> DEBUG_OUT/1

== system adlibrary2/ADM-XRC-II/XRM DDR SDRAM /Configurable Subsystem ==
  cache_data_in : Inport
  cache_addr : Inport  Port=2
  cache_write : Inport  Port=3
  ddr_page : Inport  Port=4
  ddr_addr : Inport  Port=5
  ddr_read : Inport  Port=6
  ddr_write : Inport  Port=7
  DDR SDRAM 64bit Simulation : adlibrary2_ddr_xrm/DDR SDRAM 64bit Simulation  SystemSampleTime=-1  memsize=memsize
  cache_data_out : Outport
  ddr_busy : Outport  Port=2
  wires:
  cache_data_in/1 -> DDR SDRAM 64bit Simulation/1
  cache_addr/1 -> DDR SDRAM 64bit Simulation/2
  cache_write/1 -> DDR SDRAM 64bit Simulation/3
  ddr_page/1 -> DDR SDRAM 64bit Simulation/4
  ddr_addr/1 -> DDR SDRAM 64bit Simulation/5
  ddr_read/1 -> DDR SDRAM 64bit Simulation/6
  ddr_write/1 -> DDR SDRAM 64bit Simulation/7
  DDR SDRAM 64bit Simulation/1 -> cache_data_out/1
  DDR SDRAM 64bit Simulation/2 -> ddr_busy/1

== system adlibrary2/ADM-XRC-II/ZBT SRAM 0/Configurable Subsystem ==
  d : Inport
  a : Inport  Port=2
  w : Inport  Port=3
  r : Inport  Port=4
  be : Inport  Port=5
  adlocb_in : Inport  Port=6
  ZBT SRAM 32Bit Simulation : adlibrary2_zbt32_0/ZBT SRAM 32Bit Simulation  SystemSampleTime=-1
  q : Outport
  qv : Outport  Port=2
  adlocb_out : Outport  Port=3
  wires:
  d/1 -> ZBT SRAM 32Bit Simulation/1
  a/1 -> ZBT SRAM 32Bit Simulation/2
  w/1 -> ZBT SRAM 32Bit Simulation/3
  r/1 -> ZBT SRAM 32Bit Simulation/4
  be/1 -> ZBT SRAM 32Bit Simulation/5
  adlocb_in/1 -> ZBT SRAM 32Bit Simulation/6
  ZBT SRAM 32Bit Simulation/1 -> q/1
  ZBT SRAM 32Bit Simulation/2 -> qv/1
  ZBT SRAM 32Bit Simulation/3 -> adlocb_out/1

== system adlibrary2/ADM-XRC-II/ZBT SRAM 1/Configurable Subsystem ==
  d : Inport
  a : Inport  Port=2
  w : Inport  Port=3
  r : Inport  Port=4
  be : Inport  Port=5
  adlocb_in : Inport  Port=6
  ZBT SRAM 32Bit Simulation : adlibrary2_zbt32_1/ZBT SRAM 32Bit Simulation  SystemSampleTime=-1
  q : Outport
  qv : Outport  Port=2
  adlocb_out : Outport  Port=3
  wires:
  d/1 -> ZBT SRAM 32Bit Simulation/1
  a/1 -> ZBT SRAM 32Bit Simulation/2
  w/1 -> ZBT SRAM 32Bit Simulation/3
  r/1 -> ZBT SRAM 32Bit Simulation/4
  be/1 -> ZBT SRAM 32Bit Simulation/5
  adlocb_in/1 -> ZBT SRAM 32Bit Simulation/6
  ZBT SRAM 32Bit Simulation/1 -> q/1
  ZBT SRAM 32Bit Simulation/2 -> qv/1
  ZBT SRAM 32Bit Simulation/3 -> adlocb_out/1

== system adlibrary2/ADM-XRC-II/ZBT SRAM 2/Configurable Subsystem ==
  d : Inport
  a : Inport  Port=2
  w : Inport  Port=3
  r : Inport  Port=4
  be : Inport  Port=5
  adlocb_in : Inport  Port=6
  ZBT SRAM 32Bit Simulation : adlibrary2_zbt32_2/ZBT SRAM 32Bit Simulation  SystemSampleTime=-1
  q : Outport
  qv : Outport  Port=2
  adlocb_out : Outport  Port=3
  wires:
  d/1 -> ZBT SRAM 32Bit Simulation/1
  a/1 -> ZBT SRAM 32Bit Simulation/2
  w/1 -> ZBT SRAM 32Bit Simulation/3
  r/1 -> ZBT SRAM 32Bit Simulation/4
  be/1 -> ZBT SRAM 32Bit Simulation/5
  adlocb_in/1 -> ZBT SRAM 32Bit Simulation/6
  ZBT SRAM 32Bit Simulation/1 -> q/1
  ZBT SRAM 32Bit Simulation/2 -> qv/1
  ZBT SRAM 32Bit Simulation/3 -> adlocb_out/1

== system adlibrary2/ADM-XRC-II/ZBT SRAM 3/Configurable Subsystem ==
  d : Inport
  a : Inport  Port=2
  w : Inport  Port=3
  r : Inport  Port=4
  be : Inport  Port=5
  adlocb_in : Inport  Port=6
  ZBT SRAM 32Bit Simulation : adlibrary2_zbt32_3/ZBT SRAM 32Bit Simulation  SystemSampleTime=-1
  q : Outport
  qv : Outport  Port=2
  adlocb_out : Outport  Port=3
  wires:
  d/1 -> ZBT SRAM 32Bit Simulation/1
  a/1 -> ZBT SRAM 32Bit Simulation/2
  w/1 -> ZBT SRAM 32Bit Simulation/3
  r/1 -> ZBT SRAM 32Bit Simulation/4
  be/1 -> ZBT SRAM 32Bit Simulation/5
  adlocb_in/1 -> ZBT SRAM 32Bit Simulation/6
  ZBT SRAM 32Bit Simulation/1 -> q/1
  ZBT SRAM 32Bit Simulation/2 -> qv/1
  ZBT SRAM 32Bit Simulation/3 -> adlocb_out/1

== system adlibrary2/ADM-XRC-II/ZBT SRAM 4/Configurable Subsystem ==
  d : Inport
  a : Inport  Port=2
  w : Inport  Port=3
  r : Inport  Port=4
  be : Inport  Port=5
  adlocb_in : Inport  Port=6
  ZBT SRAM 32Bit Simulation : adlibrary2_zbt32_4/ZBT SRAM 32Bit Simulation  SystemSampleTime=-1
  q : Outport
  qv : Outport  Port=2
  adlocb_out : Outport  Port=3
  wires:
  d/1 -> ZBT SRAM 32Bit Simulation/1
  a/1 -> ZBT SRAM 32Bit Simulation/2
  w/1 -> ZBT SRAM 32Bit Simulation/3
  r/1 -> ZBT SRAM 32Bit Simulation/4
  be/1 -> ZBT SRAM 32Bit Simulation/5
  adlocb_in/1 -> ZBT SRAM 32Bit Simulation/6
  ZBT SRAM 32Bit Simulation/1 -> q/1
  ZBT SRAM 32Bit Simulation/2 -> qv/1
  ZBT SRAM 32Bit Simulation/3 -> adlocb_out/1

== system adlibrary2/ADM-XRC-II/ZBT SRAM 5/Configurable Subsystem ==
  d : Inport
  a : Inport  Port=2
  w : Inport  Port=3
  r : Inport  Port=4
  be : Inport  Port=5
  adlocb_in : Inport  Port=6
  ZBT SRAM 32Bit Simulation : adlibrary2_zbt32_5/ZBT SRAM 32Bit Simulation  SystemSampleTime=-1
  q : Outport
  qv : Outport  Port=2
  adlocb_out : Outport  Port=3
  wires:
  d/1 -> ZBT SRAM 32Bit Simulation/1
  a/1 -> ZBT SRAM 32Bit Simulation/2
  w/1 -> ZBT SRAM 32Bit Simulation/3
  r/1 -> ZBT SRAM 32Bit Simulation/4
  be/1 -> ZBT SRAM 32Bit Simulation/5
  adlocb_in/1 -> ZBT SRAM 32Bit Simulation/6
  ZBT SRAM 32Bit Simulation/1 -> q/1
  ZBT SRAM 32Bit Simulation/2 -> qv/1
  ZBT SRAM 32Bit Simulation/3 -> adlocb_out/1
